VERSION 5.7 ;
BUSBITCHARS "[]" ;
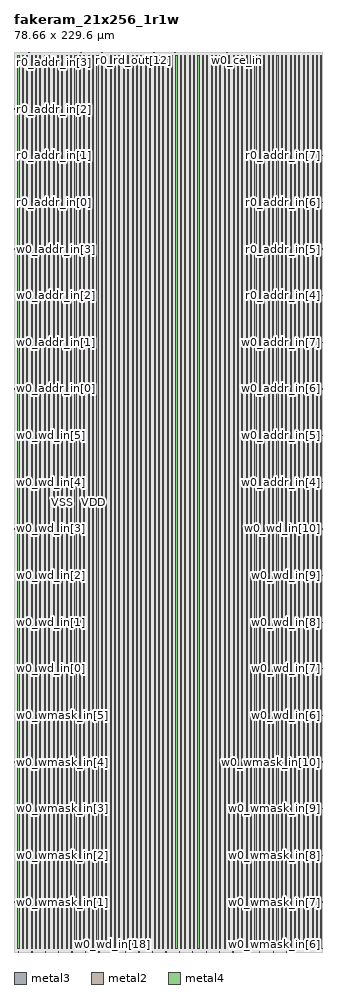
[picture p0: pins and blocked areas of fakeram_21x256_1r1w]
MACRO fakeram_21x256_1r1w
  FOREIGN fakeram_21x256_1r1w 0 0 ;
  SYMMETRY X Y R90 ;
  SIZE 78.660 BY 229.600 ;
  CLASS BLOCK ;
  PIN w0_wmask_in[0]
    DIRECTION INPUT ;
    USE SIGNAL ;
    SHAPE ABUTMENT ;
    PORT
      LAYER metal3 ;
      RECT 0.000 0.805 0.210 0.875 ;
    END
  END w0_wmask_in[0]
  PIN w0_wmask_in[1]
    DIRECTION INPUT ;
    USE SIGNAL ;
    SHAPE ABUTMENT ;
    PORT
      LAYER metal3 ;
      RECT 0.000 12.705 0.210 12.775 ;
    END
  END w0_wmask_in[1]
  PIN w0_wmask_in[2]
    DIRECTION INPUT ;
    USE SIGNAL ;
    SHAPE ABUTMENT ;
    PORT
      LAYER metal3 ;
      RECT 0.000 24.605 0.210 24.675 ;
    END
  END w0_wmask_in[2]
  PIN w0_wmask_in[3]
    DIRECTION INPUT ;
    USE SIGNAL ;
    SHAPE ABUTMENT ;
    PORT
      LAYER metal3 ;
      RECT 0.000 36.505 0.210 36.575 ;
    END
  END w0_wmask_in[3]
  PIN w0_wmask_in[4]
    DIRECTION INPUT ;
    USE SIGNAL ;
    SHAPE ABUTMENT ;
    PORT
      LAYER metal3 ;
      RECT 0.000 48.405 0.210 48.475 ;
    END
  END w0_wmask_in[4]
  PIN w0_wmask_in[5]
    DIRECTION INPUT ;
    USE SIGNAL ;
    SHAPE ABUTMENT ;
    PORT
      LAYER metal3 ;
      RECT 0.000 60.305 0.210 60.375 ;
    END
  END w0_wmask_in[5]
  PIN w0_wmask_in[6]
    DIRECTION INPUT ;
    USE SIGNAL ;
    SHAPE ABUTMENT ;
    PORT
      LAYER metal3 ;
      RECT 78.450 0.805 78.660 0.875 ;
    END
  END w0_wmask_in[6]
  PIN w0_wmask_in[7]
    DIRECTION INPUT ;
    USE SIGNAL ;
    SHAPE ABUTMENT ;
    PORT
      LAYER metal3 ;
      RECT 78.450 12.705 78.660 12.775 ;
    END
  END w0_wmask_in[7]
  PIN w0_wmask_in[8]
    DIRECTION INPUT ;
    USE SIGNAL ;
    SHAPE ABUTMENT ;
    PORT
      LAYER metal3 ;
      RECT 78.450 24.605 78.660 24.675 ;
    END
  END w0_wmask_in[8]
  PIN w0_wmask_in[9]
    DIRECTION INPUT ;
    USE SIGNAL ;
    SHAPE ABUTMENT ;
    PORT
      LAYER metal3 ;
      RECT 78.450 36.505 78.660 36.575 ;
    END
  END w0_wmask_in[9]
  PIN w0_wmask_in[10]
    DIRECTION INPUT ;
    USE SIGNAL ;
    SHAPE ABUTMENT ;
    PORT
      LAYER metal3 ;
      RECT 78.450 48.405 78.660 48.475 ;
    END
  END w0_wmask_in[10]
  PIN w0_wmask_in[11]
    DIRECTION INPUT ;
    USE SIGNAL ;
    SHAPE ABUTMENT ;
    PORT
      LAYER metal2 ;
      RECT 1.105 229.390 1.175 229.600 ;
    END
  END w0_wmask_in[11]
  PIN w0_wmask_in[12]
    DIRECTION INPUT ;
    USE SIGNAL ;
    SHAPE ABUTMENT ;
    PORT
      LAYER metal2 ;
      RECT 3.765 229.390 3.835 229.600 ;
    END
  END w0_wmask_in[12]
  PIN w0_wmask_in[13]
    DIRECTION INPUT ;
    USE SIGNAL ;
    SHAPE ABUTMENT ;
    PORT
      LAYER metal2 ;
      RECT 6.425 229.390 6.495 229.600 ;
    END
  END w0_wmask_in[13]
  PIN w0_wmask_in[14]
    DIRECTION INPUT ;
    USE SIGNAL ;
    SHAPE ABUTMENT ;
    PORT
      LAYER metal2 ;
      RECT 9.085 229.390 9.155 229.600 ;
    END
  END w0_wmask_in[14]
  PIN w0_wmask_in[15]
    DIRECTION INPUT ;
    USE SIGNAL ;
    SHAPE ABUTMENT ;
    PORT
      LAYER metal2 ;
      RECT 11.745 229.390 11.815 229.600 ;
    END
  END w0_wmask_in[15]
  PIN w0_wmask_in[16]
    DIRECTION INPUT ;
    USE SIGNAL ;
    SHAPE ABUTMENT ;
    PORT
      LAYER metal2 ;
      RECT 14.405 229.390 14.475 229.600 ;
    END
  END w0_wmask_in[16]
  PIN w0_wmask_in[17]
    DIRECTION INPUT ;
    USE SIGNAL ;
    SHAPE ABUTMENT ;
    PORT
      LAYER metal2 ;
      RECT 17.065 229.390 17.135 229.600 ;
    END
  END w0_wmask_in[17]
  PIN w0_wmask_in[18]
    DIRECTION INPUT ;
    USE SIGNAL ;
    SHAPE ABUTMENT ;
    PORT
      LAYER metal2 ;
      RECT 19.725 229.390 19.795 229.600 ;
    END
  END w0_wmask_in[18]
  PIN w0_wmask_in[19]
    DIRECTION INPUT ;
    USE SIGNAL ;
    SHAPE ABUTMENT ;
    PORT
      LAYER metal2 ;
      RECT 22.385 229.390 22.455 229.600 ;
    END
  END w0_wmask_in[19]
  PIN w0_wmask_in[20]
    DIRECTION INPUT ;
    USE SIGNAL ;
    SHAPE ABUTMENT ;
    PORT
      LAYER metal2 ;
      RECT 25.045 229.390 25.115 229.600 ;
    END
  END w0_wmask_in[20]
  PIN w0_wd_in[0]
    DIRECTION INPUT ;
    USE SIGNAL ;
    SHAPE ABUTMENT ;
    PORT
      LAYER metal3 ;
      RECT 0.000 72.205 0.210 72.275 ;
    END
  END w0_wd_in[0]
  PIN w0_wd_in[1]
    DIRECTION INPUT ;
    USE SIGNAL ;
    SHAPE ABUTMENT ;
    PORT
      LAYER metal3 ;
      RECT 0.000 84.105 0.210 84.175 ;
    END
  END w0_wd_in[1]
  PIN w0_wd_in[2]
    DIRECTION INPUT ;
    USE SIGNAL ;
    SHAPE ABUTMENT ;
    PORT
      LAYER metal3 ;
      RECT 0.000 96.005 0.210 96.075 ;
    END
  END w0_wd_in[2]
  PIN w0_wd_in[3]
    DIRECTION INPUT ;
    USE SIGNAL ;
    SHAPE ABUTMENT ;
    PORT
      LAYER metal3 ;
      RECT 0.000 107.905 0.210 107.975 ;
    END
  END w0_wd_in[3]
  PIN w0_wd_in[4]
    DIRECTION INPUT ;
    USE SIGNAL ;
    SHAPE ABUTMENT ;
    PORT
      LAYER metal3 ;
      RECT 0.000 119.805 0.210 119.875 ;
    END
  END w0_wd_in[4]
  PIN w0_wd_in[5]
    DIRECTION INPUT ;
    USE SIGNAL ;
    SHAPE ABUTMENT ;
    PORT
      LAYER metal3 ;
      RECT 0.000 131.705 0.210 131.775 ;
    END
  END w0_wd_in[5]
  PIN w0_wd_in[6]
    DIRECTION INPUT ;
    USE SIGNAL ;
    SHAPE ABUTMENT ;
    PORT
      LAYER metal3 ;
      RECT 78.450 60.305 78.660 60.375 ;
    END
  END w0_wd_in[6]
  PIN w0_wd_in[7]
    DIRECTION INPUT ;
    USE SIGNAL ;
    SHAPE ABUTMENT ;
    PORT
      LAYER metal3 ;
      RECT 78.450 72.205 78.660 72.275 ;
    END
  END w0_wd_in[7]
  PIN w0_wd_in[8]
    DIRECTION INPUT ;
    USE SIGNAL ;
    SHAPE ABUTMENT ;
    PORT
      LAYER metal3 ;
      RECT 78.450 84.105 78.660 84.175 ;
    END
  END w0_wd_in[8]
  PIN w0_wd_in[9]
    DIRECTION INPUT ;
    USE SIGNAL ;
    SHAPE ABUTMENT ;
    PORT
      LAYER metal3 ;
      RECT 78.450 96.005 78.660 96.075 ;
    END
  END w0_wd_in[9]
  PIN w0_wd_in[10]
    DIRECTION INPUT ;
    USE SIGNAL ;
    SHAPE ABUTMENT ;
    PORT
      LAYER metal3 ;
      RECT 78.450 107.905 78.660 107.975 ;
    END
  END w0_wd_in[10]
  PIN w0_wd_in[11]
    DIRECTION INPUT ;
    USE SIGNAL ;
    SHAPE ABUTMENT ;
    PORT
      LAYER metal2 ;
      RECT 1.105 0.000 1.175 0.210 ;
    END
  END w0_wd_in[11]
  PIN w0_wd_in[12]
    DIRECTION INPUT ;
    USE SIGNAL ;
    SHAPE ABUTMENT ;
    PORT
      LAYER metal2 ;
      RECT 4.525 0.000 4.595 0.210 ;
    END
  END w0_wd_in[12]
  PIN w0_wd_in[13]
    DIRECTION INPUT ;
    USE SIGNAL ;
    SHAPE ABUTMENT ;
    PORT
      LAYER metal2 ;
      RECT 7.945 0.000 8.015 0.210 ;
    END
  END w0_wd_in[13]
  PIN w0_wd_in[14]
    DIRECTION INPUT ;
    USE SIGNAL ;
    SHAPE ABUTMENT ;
    PORT
      LAYER metal2 ;
      RECT 11.365 0.000 11.435 0.210 ;
    END
  END w0_wd_in[14]
  PIN w0_wd_in[15]
    DIRECTION INPUT ;
    USE SIGNAL ;
    SHAPE ABUTMENT ;
    PORT
      LAYER metal2 ;
      RECT 14.785 0.000 14.855 0.210 ;
    END
  END w0_wd_in[15]
  PIN w0_wd_in[16]
    DIRECTION INPUT ;
    USE SIGNAL ;
    SHAPE ABUTMENT ;
    PORT
      LAYER metal2 ;
      RECT 18.205 0.000 18.275 0.210 ;
    END
  END w0_wd_in[16]
  PIN w0_wd_in[17]
    DIRECTION INPUT ;
    USE SIGNAL ;
    SHAPE ABUTMENT ;
    PORT
      LAYER metal2 ;
      RECT 21.625 0.000 21.695 0.210 ;
    END
  END w0_wd_in[17]
  PIN w0_wd_in[18]
    DIRECTION INPUT ;
    USE SIGNAL ;
    SHAPE ABUTMENT ;
    PORT
      LAYER metal2 ;
      RECT 25.045 0.000 25.115 0.210 ;
    END
  END w0_wd_in[18]
  PIN w0_wd_in[19]
    DIRECTION INPUT ;
    USE SIGNAL ;
    SHAPE ABUTMENT ;
    PORT
      LAYER metal2 ;
      RECT 28.465 0.000 28.535 0.210 ;
    END
  END w0_wd_in[19]
  PIN w0_wd_in[20]
    DIRECTION INPUT ;
    USE SIGNAL ;
    SHAPE ABUTMENT ;
    PORT
      LAYER metal2 ;
      RECT 31.885 0.000 31.955 0.210 ;
    END
  END w0_wd_in[20]
  PIN r0_rd_out[0]
    DIRECTION OUTPUT ;
    USE SIGNAL ;
    SHAPE ABUTMENT ;
    PORT
      LAYER metal2 ;
      RECT 35.305 0.000 35.375 0.210 ;
    END
  END r0_rd_out[0]
  PIN r0_rd_out[1]
    DIRECTION OUTPUT ;
    USE SIGNAL ;
    SHAPE ABUTMENT ;
    PORT
      LAYER metal2 ;
      RECT 38.725 0.000 38.795 0.210 ;
    END
  END r0_rd_out[1]
  PIN r0_rd_out[2]
    DIRECTION OUTPUT ;
    USE SIGNAL ;
    SHAPE ABUTMENT ;
    PORT
      LAYER metal2 ;
      RECT 42.145 0.000 42.215 0.210 ;
    END
  END r0_rd_out[2]
  PIN r0_rd_out[3]
    DIRECTION OUTPUT ;
    USE SIGNAL ;
    SHAPE ABUTMENT ;
    PORT
      LAYER metal2 ;
      RECT 45.565 0.000 45.635 0.210 ;
    END
  END r0_rd_out[3]
  PIN r0_rd_out[4]
    DIRECTION OUTPUT ;
    USE SIGNAL ;
    SHAPE ABUTMENT ;
    PORT
      LAYER metal2 ;
      RECT 48.985 0.000 49.055 0.210 ;
    END
  END r0_rd_out[4]
  PIN r0_rd_out[5]
    DIRECTION OUTPUT ;
    USE SIGNAL ;
    SHAPE ABUTMENT ;
    PORT
      LAYER metal2 ;
      RECT 52.405 0.000 52.475 0.210 ;
    END
  END r0_rd_out[5]
  PIN r0_rd_out[6]
    DIRECTION OUTPUT ;
    USE SIGNAL ;
    SHAPE ABUTMENT ;
    PORT
      LAYER metal2 ;
      RECT 55.825 0.000 55.895 0.210 ;
    END
  END r0_rd_out[6]
  PIN r0_rd_out[7]
    DIRECTION OUTPUT ;
    USE SIGNAL ;
    SHAPE ABUTMENT ;
    PORT
      LAYER metal2 ;
      RECT 59.245 0.000 59.315 0.210 ;
    END
  END r0_rd_out[7]
  PIN r0_rd_out[8]
    DIRECTION OUTPUT ;
    USE SIGNAL ;
    SHAPE ABUTMENT ;
    PORT
      LAYER metal2 ;
      RECT 62.665 0.000 62.735 0.210 ;
    END
  END r0_rd_out[8]
  PIN r0_rd_out[9]
    DIRECTION OUTPUT ;
    USE SIGNAL ;
    SHAPE ABUTMENT ;
    PORT
      LAYER metal2 ;
      RECT 66.085 0.000 66.155 0.210 ;
    END
  END r0_rd_out[9]
  PIN r0_rd_out[10]
    DIRECTION OUTPUT ;
    USE SIGNAL ;
    SHAPE ABUTMENT ;
    PORT
      LAYER metal2 ;
      RECT 69.505 0.000 69.575 0.210 ;
    END
  END r0_rd_out[10]
  PIN r0_rd_out[11]
    DIRECTION OUTPUT ;
    USE SIGNAL ;
    SHAPE ABUTMENT ;
    PORT
      LAYER metal2 ;
      RECT 27.705 229.390 27.775 229.600 ;
    END
  END r0_rd_out[11]
  PIN r0_rd_out[12]
    DIRECTION OUTPUT ;
    USE SIGNAL ;
    SHAPE ABUTMENT ;
    PORT
      LAYER metal2 ;
      RECT 30.365 229.390 30.435 229.600 ;
    END
  END r0_rd_out[12]
  PIN r0_rd_out[13]
    DIRECTION OUTPUT ;
    USE SIGNAL ;
    SHAPE ABUTMENT ;
    PORT
      LAYER metal2 ;
      RECT 33.025 229.390 33.095 229.600 ;
    END
  END r0_rd_out[13]
  PIN r0_rd_out[14]
    DIRECTION OUTPUT ;
    USE SIGNAL ;
    SHAPE ABUTMENT ;
    PORT
      LAYER metal2 ;
      RECT 35.685 229.390 35.755 229.600 ;
    END
  END r0_rd_out[14]
  PIN r0_rd_out[15]
    DIRECTION OUTPUT ;
    USE SIGNAL ;
    SHAPE ABUTMENT ;
    PORT
      LAYER metal2 ;
      RECT 38.345 229.390 38.415 229.600 ;
    END
  END r0_rd_out[15]
  PIN r0_rd_out[16]
    DIRECTION OUTPUT ;
    USE SIGNAL ;
    SHAPE ABUTMENT ;
    PORT
      LAYER metal2 ;
      RECT 41.005 229.390 41.075 229.600 ;
    END
  END r0_rd_out[16]
  PIN r0_rd_out[17]
    DIRECTION OUTPUT ;
    USE SIGNAL ;
    SHAPE ABUTMENT ;
    PORT
      LAYER metal2 ;
      RECT 43.665 229.390 43.735 229.600 ;
    END
  END r0_rd_out[17]
  PIN r0_rd_out[18]
    DIRECTION OUTPUT ;
    USE SIGNAL ;
    SHAPE ABUTMENT ;
    PORT
      LAYER metal2 ;
      RECT 46.325 229.390 46.395 229.600 ;
    END
  END r0_rd_out[18]
  PIN r0_rd_out[19]
    DIRECTION OUTPUT ;
    USE SIGNAL ;
    SHAPE ABUTMENT ;
    PORT
      LAYER metal2 ;
      RECT 48.985 229.390 49.055 229.600 ;
    END
  END r0_rd_out[19]
  PIN r0_rd_out[20]
    DIRECTION OUTPUT ;
    USE SIGNAL ;
    SHAPE ABUTMENT ;
    PORT
      LAYER metal2 ;
      RECT 51.645 229.390 51.715 229.600 ;
    END
  END r0_rd_out[20]
  PIN w0_addr_in[0]
    DIRECTION INPUT ;
    USE SIGNAL ;
    SHAPE ABUTMENT ;
    PORT
      LAYER metal3 ;
      RECT 0.000 143.605 0.210 143.675 ;
    END
  END w0_addr_in[0]
  PIN w0_addr_in[1]
    DIRECTION INPUT ;
    USE SIGNAL ;
    SHAPE ABUTMENT ;
    PORT
      LAYER metal3 ;
      RECT 0.000 155.505 0.210 155.575 ;
    END
  END w0_addr_in[1]
  PIN w0_addr_in[2]
    DIRECTION INPUT ;
    USE SIGNAL ;
    SHAPE ABUTMENT ;
    PORT
      LAYER metal3 ;
      RECT 0.000 167.405 0.210 167.475 ;
    END
  END w0_addr_in[2]
  PIN w0_addr_in[3]
    DIRECTION INPUT ;
    USE SIGNAL ;
    SHAPE ABUTMENT ;
    PORT
      LAYER metal3 ;
      RECT 0.000 179.305 0.210 179.375 ;
    END
  END w0_addr_in[3]
  PIN w0_addr_in[4]
    DIRECTION INPUT ;
    USE SIGNAL ;
    SHAPE ABUTMENT ;
    PORT
      LAYER metal3 ;
      RECT 78.450 119.805 78.660 119.875 ;
    END
  END w0_addr_in[4]
  PIN w0_addr_in[5]
    DIRECTION INPUT ;
    USE SIGNAL ;
    SHAPE ABUTMENT ;
    PORT
      LAYER metal3 ;
      RECT 78.450 131.705 78.660 131.775 ;
    END
  END w0_addr_in[5]
  PIN w0_addr_in[6]
    DIRECTION INPUT ;
    USE SIGNAL ;
    SHAPE ABUTMENT ;
    PORT
      LAYER metal3 ;
      RECT 78.450 143.605 78.660 143.675 ;
    END
  END w0_addr_in[6]
  PIN w0_addr_in[7]
    DIRECTION INPUT ;
    USE SIGNAL ;
    SHAPE ABUTMENT ;
    PORT
      LAYER metal3 ;
      RECT 78.450 155.505 78.660 155.575 ;
    END
  END w0_addr_in[7]
  PIN r0_addr_in[0]
    DIRECTION INPUT ;
    USE SIGNAL ;
    SHAPE ABUTMENT ;
    PORT
      LAYER metal3 ;
      RECT 0.000 191.205 0.210 191.275 ;
    END
  END r0_addr_in[0]
  PIN r0_addr_in[1]
    DIRECTION INPUT ;
    USE SIGNAL ;
    SHAPE ABUTMENT ;
    PORT
      LAYER metal3 ;
      RECT 0.000 203.105 0.210 203.175 ;
    END
  END r0_addr_in[1]
  PIN r0_addr_in[2]
    DIRECTION INPUT ;
    USE SIGNAL ;
    SHAPE ABUTMENT ;
    PORT
      LAYER metal3 ;
      RECT 0.000 215.005 0.210 215.075 ;
    END
  END r0_addr_in[2]
  PIN r0_addr_in[3]
    DIRECTION INPUT ;
    USE SIGNAL ;
    SHAPE ABUTMENT ;
    PORT
      LAYER metal3 ;
      RECT 0.000 226.905 0.210 226.975 ;
    END
  END r0_addr_in[3]
  PIN r0_addr_in[4]
    DIRECTION INPUT ;
    USE SIGNAL ;
    SHAPE ABUTMENT ;
    PORT
      LAYER metal3 ;
      RECT 78.450 167.405 78.660 167.475 ;
    END
  END r0_addr_in[4]
  PIN r0_addr_in[5]
    DIRECTION INPUT ;
    USE SIGNAL ;
    SHAPE ABUTMENT ;
    PORT
      LAYER metal3 ;
      RECT 78.450 179.305 78.660 179.375 ;
    END
  END r0_addr_in[5]
  PIN r0_addr_in[6]
    DIRECTION INPUT ;
    USE SIGNAL ;
    SHAPE ABUTMENT ;
    PORT
      LAYER metal3 ;
      RECT 78.450 191.205 78.660 191.275 ;
    END
  END r0_addr_in[6]
  PIN r0_addr_in[7]
    DIRECTION INPUT ;
    USE SIGNAL ;
    SHAPE ABUTMENT ;
    PORT
      LAYER metal3 ;
      RECT 78.450 203.105 78.660 203.175 ;
    END
  END r0_addr_in[7]
  PIN w0_we_in
    DIRECTION INPUT ;
    USE SIGNAL ;
    SHAPE ABUTMENT ;
    PORT
      LAYER metal2 ;
      RECT 54.305 229.390 54.375 229.600 ;
    END
  END w0_we_in
  PIN w0_ce_in
    DIRECTION INPUT ;
    USE SIGNAL ;
    SHAPE ABUTMENT ;
    PORT
      LAYER metal2 ;
      RECT 56.965 229.390 57.035 229.600 ;
    END
  END w0_ce_in
  PIN w0_clk
    DIRECTION INPUT ;
    USE SIGNAL ;
    SHAPE ABUTMENT ;
    PORT
      LAYER metal2 ;
      RECT 59.625 229.390 59.695 229.600 ;
    END
  END w0_clk
  PIN r0_ce_in
    DIRECTION INPUT ;
    USE SIGNAL ;
    SHAPE ABUTMENT ;
    PORT
      LAYER metal2 ;
      RECT 62.285 229.390 62.355 229.600 ;
    END
  END r0_ce_in
  PIN r0_clk
    DIRECTION INPUT ;
    USE SIGNAL ;
    SHAPE ABUTMENT ;
    PORT
      LAYER metal2 ;
      RECT 64.945 229.390 65.015 229.600 ;
    END
  END r0_clk
  PIN VSS
    DIRECTION INOUT ;
    USE GROUND ;
    PORT
      LAYER metal4 ;
      RECT 1.000 0.840 1.280 228.760 ;
      RECT 3.240 0.840 3.520 228.760 ;
      RECT 5.480 0.840 5.760 228.760 ;
      RECT 7.720 0.840 8.000 228.760 ;
      RECT 9.960 0.840 10.240 228.760 ;
      RECT 12.200 0.840 12.480 228.760 ;
      RECT 14.440 0.840 14.720 228.760 ;
      RECT 16.680 0.840 16.960 228.760 ;
      RECT 18.920 0.840 19.200 228.760 ;
      RECT 21.160 0.840 21.440 228.760 ;
      RECT 23.400 0.840 23.680 228.760 ;
      RECT 25.640 0.840 25.920 228.760 ;
      RECT 27.880 0.840 28.160 228.760 ;
      RECT 30.120 0.840 30.400 228.760 ;
      RECT 32.360 0.840 32.640 228.760 ;
      RECT 34.600 0.840 34.880 228.760 ;
      RECT 36.840 0.840 37.120 228.760 ;
      RECT 39.080 0.840 39.360 228.760 ;
      RECT 41.320 0.840 41.600 228.760 ;
      RECT 43.560 0.840 43.840 228.760 ;
      RECT 45.800 0.840 46.080 228.760 ;
      RECT 48.040 0.840 48.320 228.760 ;
      RECT 50.280 0.840 50.560 228.760 ;
      RECT 52.520 0.840 52.800 228.760 ;
      RECT 54.760 0.840 55.040 228.760 ;
      RECT 57.000 0.840 57.280 228.760 ;
      RECT 59.240 0.840 59.520 228.760 ;
      RECT 61.480 0.840 61.760 228.760 ;
      RECT 63.720 0.840 64.000 228.760 ;
      RECT 65.960 0.840 66.240 228.760 ;
      RECT 68.200 0.840 68.480 228.760 ;
      RECT 70.440 0.840 70.720 228.760 ;
      RECT 72.680 0.840 72.960 228.760 ;
      RECT 74.920 0.840 75.200 228.760 ;
      RECT 77.160 0.840 77.440 228.760 ;
    END
  END VSS
  PIN VDD
    DIRECTION INOUT ;
    USE POWER ;
    PORT
      LAYER metal4 ;
      RECT 2.120 0.840 2.400 228.760 ;
      RECT 4.360 0.840 4.640 228.760 ;
      RECT 6.600 0.840 6.880 228.760 ;
      RECT 8.840 0.840 9.120 228.760 ;
      RECT 11.080 0.840 11.360 228.760 ;
      RECT 13.320 0.840 13.600 228.760 ;
      RECT 15.560 0.840 15.840 228.760 ;
      RECT 17.800 0.840 18.080 228.760 ;
      RECT 20.040 0.840 20.320 228.760 ;
      RECT 22.280 0.840 22.560 228.760 ;
      RECT 24.520 0.840 24.800 228.760 ;
      RECT 26.760 0.840 27.040 228.760 ;
      RECT 29.000 0.840 29.280 228.760 ;
      RECT 31.240 0.840 31.520 228.760 ;
      RECT 33.480 0.840 33.760 228.760 ;
      RECT 35.720 0.840 36.000 228.760 ;
      RECT 37.960 0.840 38.240 228.760 ;
      RECT 40.200 0.840 40.480 228.760 ;
      RECT 42.440 0.840 42.720 228.760 ;
      RECT 44.680 0.840 44.960 228.760 ;
      RECT 46.920 0.840 47.200 228.760 ;
      RECT 49.160 0.840 49.440 228.760 ;
      RECT 51.400 0.840 51.680 228.760 ;
      RECT 53.640 0.840 53.920 228.760 ;
      RECT 55.880 0.840 56.160 228.760 ;
      RECT 58.120 0.840 58.400 228.760 ;
      RECT 60.360 0.840 60.640 228.760 ;
      RECT 62.600 0.840 62.880 228.760 ;
      RECT 64.840 0.840 65.120 228.760 ;
      RECT 67.080 0.840 67.360 228.760 ;
      RECT 69.320 0.840 69.600 228.760 ;
      RECT 71.560 0.840 71.840 228.760 ;
      RECT 73.800 0.840 74.080 228.760 ;
      RECT 76.040 0.840 76.320 228.760 ;
      RECT 78.280 0.840 78.560 228.760 ;
    END
  END VDD
  OBS
    LAYER metal1 ;
    RECT 0 0 78.660 229.600 ;
    LAYER metal2 ;
    RECT 0 0 78.660 229.600 ;
    LAYER metal3 ;
    RECT 0 0 78.660 229.600 ;
    LAYER metal4 ;
    RECT 0 0 78.660 229.600 ;
    LAYER OVERLAP ;
    RECT 0 0 78.660 229.600 ;
  END
END fakeram_21x256_1r1w

END LIBRARY
